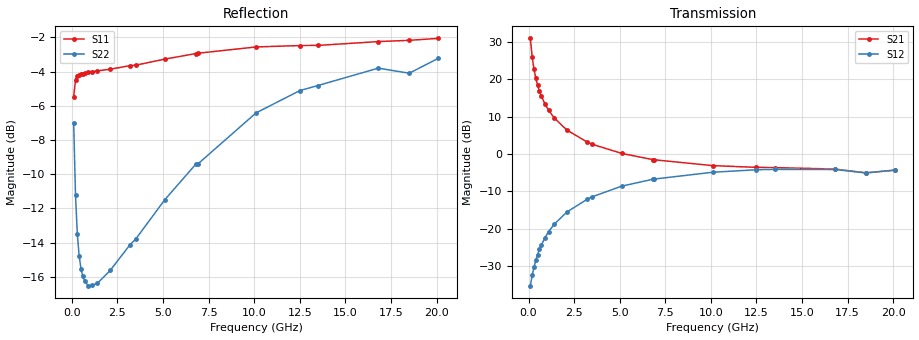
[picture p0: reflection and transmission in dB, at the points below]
!  Infineon Technologies AG
! BFR380L3 , PF131585-7, No.6, Th 09.10.01, soldered on pcb-board, measured with PP GSG850
!  Vce=1.75 V,  Ic=80.0 mA
! Common Emitter S-Parameters:  15. November 2001
#  GHz  S  MA  R  50
! f  S11  S21  S12  S22
! GHz  Mag  Ang  Mag  Ang  Mag  Ang  Mag  Ang
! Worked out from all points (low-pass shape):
!   201 points, 100 MHz to 20.1 GHz, reference 50 ohm
!   highest |S21| = 30.92 dB at 100 MHz (marker M1); lowest = -5.0 dB at 18.5 GHz (marker M2)
!   |S21| within 3 dB of the highest: start of sweep to 160.3 MHz
!   lowest |S11| = -5.5 dB at 100 MHz (marker M3), VSWR 3.29, Z = 17.8 - j19.4 ohm
!   |S11| at or under -10 dB: nowhere
!   |S22| runs from -16.5 to -3.2 dB; largest |S21 - S12| = 35
!   S11 on the Smith chart (normalised r, x): 100 MHz: 0.36, -0.39; 600 MHz: 0.23, -0.00; 3.2 GHz: 0.24, +0.37; 6.9 GHz: 0.29, +0.85; 12.5 GHz: 0.52, +1.57; 20.1 GHz: 1.04, +2.61
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0.1  0.5334 -133.0  35.17 121.3  0.01738 56.1  0.4458 -70.6
0.2  0.5966 -156.8  19.84 104.6  0.02384 57.5  0.2745 -97.6
0.3  0.6137 -166.3  13.61 97.5  0.0309 62.0  0.2116 -113.1
0.4  0.6168 -172.3  10.33 92.9  0.03795 65.4  0.1825 -124.0
0.5  0.621 -176.1  8.306 89.5  0.04539 67.7  0.1676 -132.0
0.6  0.6228 -179.5  6.952 86.7  0.05313 69.0  0.159 -138.1
0.7  0.6245 177.7  5.982 84.2  0.06056 70.1  0.1541 -143.0
0.9  0.6278 173.2  4.677 79.9  0.07609 70.6  0.1494 -150.1
1.1  0.6301 169.3  3.855 76.0  0.09161 70.6  0.1496 -154.8
1.4  0.634 163.8  3.056 70.7  0.1145 69.8  0.1518 -160.2
2.1  0.641 152.8  2.094 59.4  0.1676 66.1  0.1655 -168.3
3.2  0.6567 137.3  1.454 44.1  0.2471 58.4  0.1971 -178.8
3.5  0.6588 133.3  1.349 40.3  0.2687 56.2  0.2044 179.2
5.1  0.686 114.5  1.021 23.1  0.3716 43.8  0.2666 163.7
6.8  0.7124 97.5  0.8442 9.7  0.4594 31.2  0.3385 146.3
6.9  0.7136 96.5  0.8378 9.0  0.4631 30.4  0.3385 145.4
10.1  0.7447 73.3  0.6999 -7.7  0.5709 8.8  0.4778 118.4
12.5  0.7516 61.2  0.6638 -17.6  0.6166 -5.9  0.5552 99.4
13.5  0.7525 56.8  0.6587 -21.8  0.6234 -11.7  0.5745 92.9
16.8  0.7719 45.7  0.6295 -32.5  0.6213 -27.0  0.6456 73.5
18.5  0.7786 44.1  0.5605 -39.8  0.5588 -35.1  0.624 68.7
20.1  0.7889 37.1  0.6076 -43.5  0.6117 -40.1  0.6901 58.3
